VERSION 5.8 ;
BUSBITCHARS "[]" ;
DIVIDERCHAR "/" ;
UNITS
    DATABASE MICRONS 1000 ;
END UNITS

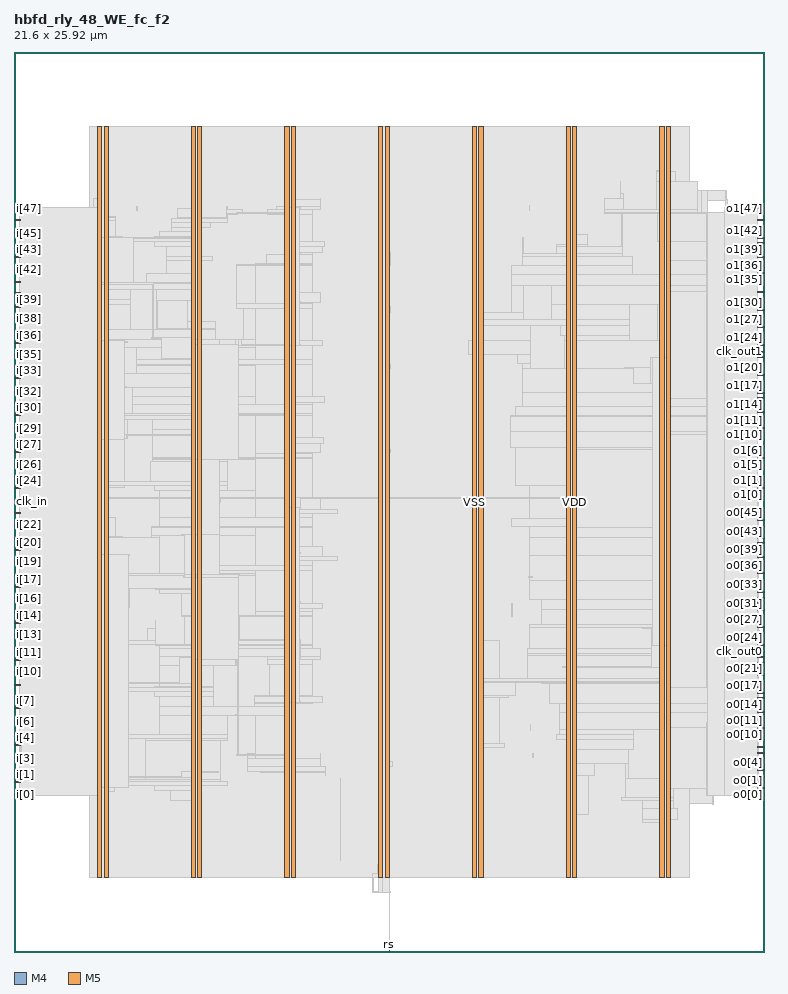
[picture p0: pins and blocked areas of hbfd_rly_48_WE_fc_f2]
MACRO hbfd_rly_48_WE_fc_f2
  FOREIGN hbfd_rly_48_WE_fc_f2 0 0 ;
  CLASS BLOCK ;
  SIZE 21.6 BY 25.92 ;
  PIN clk_in
    DIRECTION INPUT ;
    USE SIGNAL ;
    PORT
      LAYER M4 ;
        RECT  0 12.96 0.192 12.984 ;
    END
  END clk_in
  PIN clk_out0
    DIRECTION OUTPUT ;
    USE SIGNAL ;
    PORT
      LAYER M4 ;
        RECT  21.408 8.64 21.6 8.664 ;
    END
  END clk_out0
  PIN clk_out1
    DIRECTION OUTPUT ;
    USE SIGNAL ;
    PORT
      LAYER M4 ;
        RECT  21.408 17.28 21.6 17.304 ;
    END
  END clk_out1
  PIN i[0]
    DIRECTION INPUT ;
    USE SIGNAL ;
    PORT
      LAYER M4 ;
        RECT  0 4.512 0.192 4.536 ;
    END
  END i[0]
  PIN i[10]
    DIRECTION INPUT ;
    USE SIGNAL ;
    PORT
      LAYER M4 ;
        RECT  0 8.064 0.192 8.088 ;
    END
  END i[10]
  PIN i[11]
    DIRECTION INPUT ;
    USE SIGNAL ;
    PORT
      LAYER M4 ;
        RECT  0 8.4 0.192 8.424 ;
    END
  END i[11]
  PIN i[12]
    DIRECTION INPUT ;
    USE SIGNAL ;
    PORT
      LAYER M4 ;
        RECT  0 8.736 0.192 8.76 ;
    END
  END i[12]
  PIN i[13]
    DIRECTION INPUT ;
    USE SIGNAL ;
    PORT
      LAYER M4 ;
        RECT  0 9.12 0.192 9.144 ;
    END
  END i[13]
  PIN i[14]
    DIRECTION INPUT ;
    USE SIGNAL ;
    PORT
      LAYER M4 ;
        RECT  0 9.456 0.192 9.48 ;
    END
  END i[14]
  PIN i[15]
    DIRECTION INPUT ;
    USE SIGNAL ;
    PORT
      LAYER M4 ;
        RECT  0 9.792 0.192 9.816 ;
    END
  END i[15]
  PIN i[16]
    DIRECTION INPUT ;
    USE SIGNAL ;
    PORT
      LAYER M4 ;
        RECT  0 10.176 0.192 10.2 ;
    END
  END i[16]
  PIN i[17]
    DIRECTION INPUT ;
    USE SIGNAL ;
    PORT
      LAYER M4 ;
        RECT  0 10.512 0.192 10.536 ;
    END
  END i[17]
  PIN i[18]
    DIRECTION INPUT ;
    USE SIGNAL ;
    PORT
      LAYER M4 ;
        RECT  0 10.848 0.192 10.872 ;
    END
  END i[18]
  PIN i[19]
    DIRECTION INPUT ;
    USE SIGNAL ;
    PORT
      LAYER M4 ;
        RECT  0 11.232 0.192 11.256 ;
    END
  END i[19]
  PIN i[1]
    DIRECTION INPUT ;
    USE SIGNAL ;
    PORT
      LAYER M4 ;
        RECT  0 4.896 0.192 4.92 ;
    END
  END i[1]
  PIN i[20]
    DIRECTION INPUT ;
    USE SIGNAL ;
    PORT
      LAYER M4 ;
        RECT  0 11.568 0.192 11.592 ;
    END
  END i[20]
  PIN i[21]
    DIRECTION INPUT ;
    USE SIGNAL ;
    PORT
      LAYER M4 ;
        RECT  0 11.904 0.192 11.928 ;
    END
  END i[21]
  PIN i[22]
    DIRECTION INPUT ;
    USE SIGNAL ;
    PORT
      LAYER M4 ;
        RECT  0 12.288 0.192 12.312 ;
    END
  END i[22]
  PIN i[23]
    DIRECTION INPUT ;
    USE SIGNAL ;
    PORT
      LAYER M4 ;
        RECT  0 12.624 0.192 12.648 ;
    END
  END i[23]
  PIN i[24]
    DIRECTION INPUT ;
    USE SIGNAL ;
    PORT
      LAYER M4 ;
        RECT  0 13.344 0.192 13.368 ;
    END
  END i[24]
  PIN i[25]
    DIRECTION INPUT ;
    USE SIGNAL ;
    PORT
      LAYER M4 ;
        RECT  0 13.68 0.192 13.704 ;
    END
  END i[25]
  PIN i[26]
    DIRECTION INPUT ;
    USE SIGNAL ;
    PORT
      LAYER M4 ;
        RECT  0 14.016 0.192 14.04 ;
    END
  END i[26]
  PIN i[27]
    DIRECTION INPUT ;
    USE SIGNAL ;
    PORT
      LAYER M4 ;
        RECT  0 14.4 0.192 14.424 ;
    END
  END i[27]
  PIN i[28]
    DIRECTION INPUT ;
    USE SIGNAL ;
    PORT
      LAYER M4 ;
        RECT  0 14.736 0.192 14.76 ;
    END
  END i[28]
  PIN i[29]
    DIRECTION INPUT ;
    USE SIGNAL ;
    PORT
      LAYER M4 ;
        RECT  0 15.072 0.192 15.096 ;
    END
  END i[29]
  PIN i[2]
    DIRECTION INPUT ;
    USE SIGNAL ;
    PORT
      LAYER M4 ;
        RECT  0 5.232 0.192 5.256 ;
    END
  END i[2]
  PIN i[30]
    DIRECTION INPUT ;
    USE SIGNAL ;
    PORT
      LAYER M4 ;
        RECT  0 15.456 0.192 15.48 ;
    END
  END i[30]
  PIN i[31]
    DIRECTION INPUT ;
    USE SIGNAL ;
    PORT
      LAYER M4 ;
        RECT  0 15.792 0.192 15.816 ;
    END
  END i[31]
  PIN i[32]
    DIRECTION INPUT ;
    USE SIGNAL ;
    PORT
      LAYER M4 ;
        RECT  0 16.128 0.192 16.152 ;
    END
  END i[32]
  PIN i[33]
    DIRECTION INPUT ;
    USE SIGNAL ;
    PORT
      LAYER M4 ;
        RECT  0 16.512 0.192 16.536 ;
    END
  END i[33]
  PIN i[34]
    DIRECTION INPUT ;
    USE SIGNAL ;
    PORT
      LAYER M4 ;
        RECT  0 16.848 0.192 16.872 ;
    END
  END i[34]
  PIN i[35]
    DIRECTION INPUT ;
    USE SIGNAL ;
    PORT
      LAYER M4 ;
        RECT  0 17.184 0.192 17.208 ;
    END
  END i[35]
  PIN i[36]
    DIRECTION INPUT ;
    USE SIGNAL ;
    PORT
      LAYER M4 ;
        RECT  0 17.52 0.192 17.544 ;
    END
  END i[36]
  PIN i[37]
    DIRECTION INPUT ;
    USE SIGNAL ;
    PORT
      LAYER M4 ;
        RECT  0 17.904 0.192 17.928 ;
    END
  END i[37]
  PIN i[38]
    DIRECTION INPUT ;
    USE SIGNAL ;
    PORT
      LAYER M4 ;
        RECT  0 18.24 0.192 18.264 ;
    END
  END i[38]
  PIN i[39]
    DIRECTION INPUT ;
    USE SIGNAL ;
    PORT
      LAYER M4 ;
        RECT  0 18.576 0.192 18.6 ;
    END
  END i[39]
  PIN i[3]
    DIRECTION INPUT ;
    USE SIGNAL ;
    PORT
      LAYER M4 ;
        RECT  0 5.568 0.192 5.592 ;
    END
  END i[3]
  PIN i[40]
    DIRECTION INPUT ;
    USE SIGNAL ;
    PORT
      LAYER M4 ;
        RECT  0 18.96 0.192 18.984 ;
    END
  END i[40]
  PIN i[41]
    DIRECTION INPUT ;
    USE SIGNAL ;
    PORT
      LAYER M4 ;
        RECT  0 19.296 0.192 19.32 ;
    END
  END i[41]
  PIN i[42]
    DIRECTION INPUT ;
    USE SIGNAL ;
    PORT
      LAYER M4 ;
        RECT  0 19.632 0.192 19.656 ;
    END
  END i[42]
  PIN i[43]
    DIRECTION INPUT ;
    USE SIGNAL ;
    PORT
      LAYER M4 ;
        RECT  0 20.016 0.192 20.04 ;
    END
  END i[43]
  PIN i[44]
    DIRECTION INPUT ;
    USE SIGNAL ;
    PORT
      LAYER M4 ;
        RECT  0 20.352 0.192 20.376 ;
    END
  END i[44]
  PIN i[45]
    DIRECTION INPUT ;
    USE SIGNAL ;
    PORT
      LAYER M4 ;
        RECT  0 20.688 0.192 20.712 ;
    END
  END i[45]
  PIN i[46]
    DIRECTION INPUT ;
    USE SIGNAL ;
    PORT
      LAYER M4 ;
        RECT  0 21.072 0.192 21.096 ;
    END
  END i[46]
  PIN i[47]
    DIRECTION INPUT ;
    USE SIGNAL ;
    PORT
      LAYER M4 ;
        RECT  0 21.408 0.192 21.432 ;
    END
  END i[47]
  PIN i[4]
    DIRECTION INPUT ;
    USE SIGNAL ;
    PORT
      LAYER M4 ;
        RECT  0 5.952 0.192 5.976 ;
    END
  END i[4]
  PIN i[5]
    DIRECTION INPUT ;
    USE SIGNAL ;
    PORT
      LAYER M4 ;
        RECT  0 6.288 0.192 6.312 ;
    END
  END i[5]
  PIN i[6]
    DIRECTION INPUT ;
    USE SIGNAL ;
    PORT
      LAYER M4 ;
        RECT  0 6.624 0.192 6.648 ;
    END
  END i[6]
  PIN i[7]
    DIRECTION INPUT ;
    USE SIGNAL ;
    PORT
      LAYER M4 ;
        RECT  0 7.008 0.192 7.032 ;
    END
  END i[7]
  PIN i[8]
    DIRECTION INPUT ;
    USE SIGNAL ;
    PORT
      LAYER M4 ;
        RECT  0 7.344 0.192 7.368 ;
    END
  END i[8]
  PIN i[9]
    DIRECTION INPUT ;
    USE SIGNAL ;
    PORT
      LAYER M4 ;
        RECT  0 7.68 0.192 7.704 ;
    END
  END i[9]
  PIN o0[0]
    DIRECTION OUTPUT ;
    USE SIGNAL ;
    PORT
      LAYER M4 ;
        RECT  21.408 4.512 21.6 4.536 ;
    END
  END o0[0]
  PIN o0[10]
    DIRECTION OUTPUT ;
    USE SIGNAL ;
    PORT
      LAYER M4 ;
        RECT  21.408 6.24 21.6 6.264 ;
    END
  END o0[10]
  PIN o0[11]
    DIRECTION OUTPUT ;
    USE SIGNAL ;
    PORT
      LAYER M4 ;
        RECT  21.408 6.432 21.6 6.456 ;
    END
  END o0[11]
  PIN o0[12]
    DIRECTION OUTPUT ;
    USE SIGNAL ;
    PORT
      LAYER M4 ;
        RECT  21.408 6.576 21.6 6.6 ;
    END
  END o0[12]
  PIN o0[13]
    DIRECTION OUTPUT ;
    USE SIGNAL ;
    PORT
      LAYER M4 ;
        RECT  21.408 6.768 21.6 6.792 ;
    END
  END o0[13]
  PIN o0[14]
    DIRECTION OUTPUT ;
    USE SIGNAL ;
    PORT
      LAYER M4 ;
        RECT  21.408 6.912 21.6 6.936 ;
    END
  END o0[14]
  PIN o0[15]
    DIRECTION OUTPUT ;
    USE SIGNAL ;
    PORT
      LAYER M4 ;
        RECT  21.408 7.104 21.6 7.128 ;
    END
  END o0[15]
  PIN o0[16]
    DIRECTION OUTPUT ;
    USE SIGNAL ;
    PORT
      LAYER M4 ;
        RECT  21.408 7.296 21.6 7.32 ;
    END
  END o0[16]
  PIN o0[17]
    DIRECTION OUTPUT ;
    USE SIGNAL ;
    PORT
      LAYER M4 ;
        RECT  21.408 7.44 21.6 7.464 ;
    END
  END o0[17]
  PIN o0[18]
    DIRECTION OUTPUT ;
    USE SIGNAL ;
    PORT
      LAYER M4 ;
        RECT  21.408 7.632 21.6 7.656 ;
    END
  END o0[18]
  PIN o0[19]
    DIRECTION OUTPUT ;
    USE SIGNAL ;
    PORT
      LAYER M4 ;
        RECT  21.408 7.776 21.6 7.8 ;
    END
  END o0[19]
  PIN o0[1]
    DIRECTION OUTPUT ;
    USE SIGNAL ;
    PORT
      LAYER M4 ;
        RECT  21.408 4.704 21.6 4.728 ;
    END
  END o0[1]
  PIN o0[20]
    DIRECTION OUTPUT ;
    USE SIGNAL ;
    PORT
      LAYER M4 ;
        RECT  21.408 7.968 21.6 7.992 ;
    END
  END o0[20]
  PIN o0[21]
    DIRECTION OUTPUT ;
    USE SIGNAL ;
    PORT
      LAYER M4 ;
        RECT  21.408 8.16 21.6 8.184 ;
    END
  END o0[21]
  PIN o0[22]
    DIRECTION OUTPUT ;
    USE SIGNAL ;
    PORT
      LAYER M4 ;
        RECT  21.408 8.304 21.6 8.328 ;
    END
  END o0[22]
  PIN o0[23]
    DIRECTION OUTPUT ;
    USE SIGNAL ;
    PORT
      LAYER M4 ;
        RECT  21.408 8.496 21.6 8.52 ;
    END
  END o0[23]
  PIN o0[24]
    DIRECTION OUTPUT ;
    USE SIGNAL ;
    PORT
      LAYER M4 ;
        RECT  21.408 8.832 21.6 8.856 ;
    END
  END o0[24]
  PIN o0[25]
    DIRECTION OUTPUT ;
    USE SIGNAL ;
    PORT
      LAYER M4 ;
        RECT  21.408 8.976 21.6 9 ;
    END
  END o0[25]
  PIN o0[26]
    DIRECTION OUTPUT ;
    USE SIGNAL ;
    PORT
      LAYER M4 ;
        RECT  21.408 9.168 21.6 9.192 ;
    END
  END o0[26]
  PIN o0[27]
    DIRECTION OUTPUT ;
    USE SIGNAL ;
    PORT
      LAYER M4 ;
        RECT  21.408 9.36 21.6 9.384 ;
    END
  END o0[27]
  PIN o0[28]
    DIRECTION OUTPUT ;
    USE SIGNAL ;
    PORT
      LAYER M4 ;
        RECT  21.408 9.504 21.6 9.528 ;
    END
  END o0[28]
  PIN o0[29]
    DIRECTION OUTPUT ;
    USE SIGNAL ;
    PORT
      LAYER M4 ;
        RECT  21.408 9.696 21.6 9.72 ;
    END
  END o0[29]
  PIN o0[2]
    DIRECTION OUTPUT ;
    USE SIGNAL ;
    PORT
      LAYER M4 ;
        RECT  21.408 4.896 21.6 4.92 ;
    END
  END o0[2]
  PIN o0[30]
    DIRECTION OUTPUT ;
    USE SIGNAL ;
    PORT
      LAYER M4 ;
        RECT  21.408 9.84 21.6 9.864 ;
    END
  END o0[30]
  PIN o0[31]
    DIRECTION OUTPUT ;
    USE SIGNAL ;
    PORT
      LAYER M4 ;
        RECT  21.408 10.032 21.6 10.056 ;
    END
  END o0[31]
  PIN o0[32]
    DIRECTION OUTPUT ;
    USE SIGNAL ;
    PORT
      LAYER M4 ;
        RECT  21.408 10.176 21.6 10.2 ;
    END
  END o0[32]
  PIN o0[33]
    DIRECTION OUTPUT ;
    USE SIGNAL ;
    PORT
      LAYER M4 ;
        RECT  21.408 10.368 21.6 10.392 ;
    END
  END o0[33]
  PIN o0[34]
    DIRECTION OUTPUT ;
    USE SIGNAL ;
    PORT
      LAYER M4 ;
        RECT  21.408 10.56 21.6 10.584 ;
    END
  END o0[34]
  PIN o0[35]
    DIRECTION OUTPUT ;
    USE SIGNAL ;
    PORT
      LAYER M4 ;
        RECT  21.408 10.704 21.6 10.728 ;
    END
  END o0[35]
  PIN o0[36]
    DIRECTION OUTPUT ;
    USE SIGNAL ;
    PORT
      LAYER M4 ;
        RECT  21.408 10.896 21.6 10.92 ;
    END
  END o0[36]
  PIN o0[37]
    DIRECTION OUTPUT ;
    USE SIGNAL ;
    PORT
      LAYER M4 ;
        RECT  21.408 11.04 21.6 11.064 ;
    END
  END o0[37]
  PIN o0[38]
    DIRECTION OUTPUT ;
    USE SIGNAL ;
    PORT
      LAYER M4 ;
        RECT  21.408 11.232 21.6 11.256 ;
    END
  END o0[38]
  PIN o0[39]
    DIRECTION OUTPUT ;
    USE SIGNAL ;
    PORT
      LAYER M4 ;
        RECT  21.408 11.376 21.6 11.4 ;
    END
  END o0[39]
  PIN o0[3]
    DIRECTION OUTPUT ;
    USE SIGNAL ;
    PORT
      LAYER M4 ;
        RECT  21.408 5.04 21.6 5.064 ;
    END
  END o0[3]
  PIN o0[40]
    DIRECTION OUTPUT ;
    USE SIGNAL ;
    PORT
      LAYER M4 ;
        RECT  21.408 11.568 21.6 11.592 ;
    END
  END o0[40]
  PIN o0[41]
    DIRECTION OUTPUT ;
    USE SIGNAL ;
    PORT
      LAYER M4 ;
        RECT  21.408 11.76 21.6 11.784 ;
    END
  END o0[41]
  PIN o0[42]
    DIRECTION OUTPUT ;
    USE SIGNAL ;
    PORT
      LAYER M4 ;
        RECT  21.408 11.904 21.6 11.928 ;
    END
  END o0[42]
  PIN o0[43]
    DIRECTION OUTPUT ;
    USE SIGNAL ;
    PORT
      LAYER M4 ;
        RECT  21.408 12.096 21.6 12.12 ;
    END
  END o0[43]
  PIN o0[44]
    DIRECTION OUTPUT ;
    USE SIGNAL ;
    PORT
      LAYER M4 ;
        RECT  21.408 12.24 21.6 12.264 ;
    END
  END o0[44]
  PIN o0[45]
    DIRECTION OUTPUT ;
    USE SIGNAL ;
    PORT
      LAYER M4 ;
        RECT  21.408 12.432 21.6 12.456 ;
    END
  END o0[45]
  PIN o0[46]
    DIRECTION OUTPUT ;
    USE SIGNAL ;
    PORT
      LAYER M4 ;
        RECT  21.408 12.624 21.6 12.648 ;
    END
  END o0[46]
  PIN o0[47]
    DIRECTION OUTPUT ;
    USE SIGNAL ;
    PORT
      LAYER M4 ;
        RECT  21.408 12.768 21.6 12.792 ;
    END
  END o0[47]
  PIN o0[4]
    DIRECTION OUTPUT ;
    USE SIGNAL ;
    PORT
      LAYER M4 ;
        RECT  21.408 5.232 21.6 5.256 ;
    END
  END o0[4]
  PIN o0[5]
    DIRECTION OUTPUT ;
    USE SIGNAL ;
    PORT
      LAYER M4 ;
        RECT  21.408 5.376 21.6 5.4 ;
    END
  END o0[5]
  PIN o0[6]
    DIRECTION OUTPUT ;
    USE SIGNAL ;
    PORT
      LAYER M4 ;
        RECT  21.408 5.568 21.6 5.592 ;
    END
  END o0[6]
  PIN o0[7]
    DIRECTION OUTPUT ;
    USE SIGNAL ;
    PORT
      LAYER M4 ;
        RECT  21.408 5.712 21.6 5.736 ;
    END
  END o0[7]
  PIN o0[8]
    DIRECTION OUTPUT ;
    USE SIGNAL ;
    PORT
      LAYER M4 ;
        RECT  21.408 5.904 21.6 5.928 ;
    END
  END o0[8]
  PIN o0[9]
    DIRECTION OUTPUT ;
    USE SIGNAL ;
    PORT
      LAYER M4 ;
        RECT  21.408 6.096 21.6 6.12 ;
    END
  END o0[9]
  PIN o1[0]
    DIRECTION OUTPUT ;
    USE SIGNAL ;
    PORT
      LAYER M4 ;
        RECT  21.408 13.152 21.6 13.176 ;
    END
  END o1[0]
  PIN o1[10]
    DIRECTION OUTPUT ;
    USE SIGNAL ;
    PORT
      LAYER M4 ;
        RECT  21.408 14.88 21.6 14.904 ;
    END
  END o1[10]
  PIN o1[11]
    DIRECTION OUTPUT ;
    USE SIGNAL ;
    PORT
      LAYER M4 ;
        RECT  21.408 15.072 21.6 15.096 ;
    END
  END o1[11]
  PIN o1[12]
    DIRECTION OUTPUT ;
    USE SIGNAL ;
    PORT
      LAYER M4 ;
        RECT  21.408 15.216 21.6 15.24 ;
    END
  END o1[12]
  PIN o1[13]
    DIRECTION OUTPUT ;
    USE SIGNAL ;
    PORT
      LAYER M4 ;
        RECT  21.408 15.408 21.6 15.432 ;
    END
  END o1[13]
  PIN o1[14]
    DIRECTION OUTPUT ;
    USE SIGNAL ;
    PORT
      LAYER M4 ;
        RECT  21.408 15.552 21.6 15.576 ;
    END
  END o1[14]
  PIN o1[15]
    DIRECTION OUTPUT ;
    USE SIGNAL ;
    PORT
      LAYER M4 ;
        RECT  21.408 15.744 21.6 15.768 ;
    END
  END o1[15]
  PIN o1[16]
    DIRECTION OUTPUT ;
    USE SIGNAL ;
    PORT
      LAYER M4 ;
        RECT  21.408 15.936 21.6 15.96 ;
    END
  END o1[16]
  PIN o1[17]
    DIRECTION OUTPUT ;
    USE SIGNAL ;
    PORT
      LAYER M4 ;
        RECT  21.408 16.08 21.6 16.104 ;
    END
  END o1[17]
  PIN o1[18]
    DIRECTION OUTPUT ;
    USE SIGNAL ;
    PORT
      LAYER M4 ;
        RECT  21.408 16.272 21.6 16.296 ;
    END
  END o1[18]
  PIN o1[19]
    DIRECTION OUTPUT ;
    USE SIGNAL ;
    PORT
      LAYER M4 ;
        RECT  21.408 16.416 21.6 16.44 ;
    END
  END o1[19]
  PIN o1[1]
    DIRECTION OUTPUT ;
    USE SIGNAL ;
    PORT
      LAYER M4 ;
        RECT  21.408 13.344 21.6 13.368 ;
    END
  END o1[1]
  PIN o1[20]
    DIRECTION OUTPUT ;
    USE SIGNAL ;
    PORT
      LAYER M4 ;
        RECT  21.408 16.608 21.6 16.632 ;
    END
  END o1[20]
  PIN o1[21]
    DIRECTION OUTPUT ;
    USE SIGNAL ;
    PORT
      LAYER M4 ;
        RECT  21.408 16.8 21.6 16.824 ;
    END
  END o1[21]
  PIN o1[22]
    DIRECTION OUTPUT ;
    USE SIGNAL ;
    PORT
      LAYER M4 ;
        RECT  21.408 16.944 21.6 16.968 ;
    END
  END o1[22]
  PIN o1[23]
    DIRECTION OUTPUT ;
    USE SIGNAL ;
    PORT
      LAYER M4 ;
        RECT  21.408 17.136 21.6 17.16 ;
    END
  END o1[23]
  PIN o1[24]
    DIRECTION OUTPUT ;
    USE SIGNAL ;
    PORT
      LAYER M4 ;
        RECT  21.408 17.472 21.6 17.496 ;
    END
  END o1[24]
  PIN o1[25]
    DIRECTION OUTPUT ;
    USE SIGNAL ;
    PORT
      LAYER M4 ;
        RECT  21.408 17.616 21.6 17.64 ;
    END
  END o1[25]
  PIN o1[26]
    DIRECTION OUTPUT ;
    USE SIGNAL ;
    PORT
      LAYER M4 ;
        RECT  21.408 17.808 21.6 17.832 ;
    END
  END o1[26]
  PIN o1[27]
    DIRECTION OUTPUT ;
    USE SIGNAL ;
    PORT
      LAYER M4 ;
        RECT  21.408 18 21.6 18.024 ;
    END
  END o1[27]
  PIN o1[28]
    DIRECTION OUTPUT ;
    USE SIGNAL ;
    PORT
      LAYER M4 ;
        RECT  21.408 18.144 21.6 18.168 ;
    END
  END o1[28]
  PIN o1[29]
    DIRECTION OUTPUT ;
    USE SIGNAL ;
    PORT
      LAYER M4 ;
        RECT  21.408 18.336 21.6 18.36 ;
    END
  END o1[29]
  PIN o1[2]
    DIRECTION OUTPUT ;
    USE SIGNAL ;
    PORT
      LAYER M4 ;
        RECT  21.408 13.536 21.6 13.56 ;
    END
  END o1[2]
  PIN o1[30]
    DIRECTION OUTPUT ;
    USE SIGNAL ;
    PORT
      LAYER M4 ;
        RECT  21.408 18.48 21.6 18.504 ;
    END
  END o1[30]
  PIN o1[31]
    DIRECTION OUTPUT ;
    USE SIGNAL ;
    PORT
      LAYER M4 ;
        RECT  21.408 18.672 21.6 18.696 ;
    END
  END o1[31]
  PIN o1[32]
    DIRECTION OUTPUT ;
    USE SIGNAL ;
    PORT
      LAYER M4 ;
        RECT  21.408 18.816 21.6 18.84 ;
    END
  END o1[32]
  PIN o1[33]
    DIRECTION OUTPUT ;
    USE SIGNAL ;
    PORT
      LAYER M4 ;
        RECT  21.408 19.008 21.6 19.032 ;
    END
  END o1[33]
  PIN o1[34]
    DIRECTION OUTPUT ;
    USE SIGNAL ;
    PORT
      LAYER M4 ;
        RECT  21.408 19.2 21.6 19.224 ;
    END
  END o1[34]
  PIN o1[35]
    DIRECTION OUTPUT ;
    USE SIGNAL ;
    PORT
      LAYER M4 ;
        RECT  21.408 19.344 21.6 19.368 ;
    END
  END o1[35]
  PIN o1[36]
    DIRECTION OUTPUT ;
    USE SIGNAL ;
    PORT
      LAYER M4 ;
        RECT  21.408 19.536 21.6 19.56 ;
    END
  END o1[36]
  PIN o1[37]
    DIRECTION OUTPUT ;
    USE SIGNAL ;
    PORT
      LAYER M4 ;
        RECT  21.408 19.68 21.6 19.704 ;
    END
  END o1[37]
  PIN o1[38]
    DIRECTION OUTPUT ;
    USE SIGNAL ;
    PORT
      LAYER M4 ;
        RECT  21.408 19.872 21.6 19.896 ;
    END
  END o1[38]
  PIN o1[39]
    DIRECTION OUTPUT ;
    USE SIGNAL ;
    PORT
      LAYER M4 ;
        RECT  21.408 20.016 21.6 20.04 ;
    END
  END o1[39]
  PIN o1[3]
    DIRECTION OUTPUT ;
    USE SIGNAL ;
    PORT
      LAYER M4 ;
        RECT  21.408 13.68 21.6 13.704 ;
    END
  END o1[3]
  PIN o1[40]
    DIRECTION OUTPUT ;
    USE SIGNAL ;
    PORT
      LAYER M4 ;
        RECT  21.408 20.208 21.6 20.232 ;
    END
  END o1[40]
  PIN o1[41]
    DIRECTION OUTPUT ;
    USE SIGNAL ;
    PORT
      LAYER M4 ;
        RECT  21.408 20.4 21.6 20.424 ;
    END
  END o1[41]
  PIN o1[42]
    DIRECTION OUTPUT ;
    USE SIGNAL ;
    PORT
      LAYER M4 ;
        RECT  21.408 20.544 21.6 20.568 ;
    END
  END o1[42]
  PIN o1[43]
    DIRECTION OUTPUT ;
    USE SIGNAL ;
    PORT
      LAYER M4 ;
        RECT  21.408 20.736 21.6 20.76 ;
    END
  END o1[43]
  PIN o1[44]
    DIRECTION OUTPUT ;
    USE SIGNAL ;
    PORT
      LAYER M4 ;
        RECT  21.408 20.88 21.6 20.904 ;
    END
  END o1[44]
  PIN o1[45]
    DIRECTION OUTPUT ;
    USE SIGNAL ;
    PORT
      LAYER M4 ;
        RECT  21.408 21.072 21.6 21.096 ;
    END
  END o1[45]
  PIN o1[46]
    DIRECTION OUTPUT ;
    USE SIGNAL ;
    PORT
      LAYER M4 ;
        RECT  21.408 21.264 21.6 21.288 ;
    END
  END o1[46]
  PIN o1[47]
    DIRECTION OUTPUT ;
    USE SIGNAL ;
    PORT
      LAYER M4 ;
        RECT  21.408 21.408 21.6 21.432 ;
    END
  END o1[47]
  PIN o1[4]
    DIRECTION OUTPUT ;
    USE SIGNAL ;
    PORT
      LAYER M4 ;
        RECT  21.408 13.872 21.6 13.896 ;
    END
  END o1[4]
  PIN o1[5]
    DIRECTION OUTPUT ;
    USE SIGNAL ;
    PORT
      LAYER M4 ;
        RECT  21.408 14.016 21.6 14.04 ;
    END
  END o1[5]
  PIN o1[6]
    DIRECTION OUTPUT ;
    USE SIGNAL ;
    PORT
      LAYER M4 ;
        RECT  21.408 14.208 21.6 14.232 ;
    END
  END o1[6]
  PIN o1[7]
    DIRECTION OUTPUT ;
    USE SIGNAL ;
    PORT
      LAYER M4 ;
        RECT  21.408 14.352 21.6 14.376 ;
    END
  END o1[7]
  PIN o1[8]
    DIRECTION OUTPUT ;
    USE SIGNAL ;
    PORT
      LAYER M4 ;
        RECT  21.408 14.544 21.6 14.568 ;
    END
  END o1[8]
  PIN o1[9]
    DIRECTION OUTPUT ;
    USE SIGNAL ;
    PORT
      LAYER M4 ;
        RECT  21.408 14.736 21.6 14.76 ;
    END
  END o1[9]
  PIN rs
    DIRECTION INPUT ;
    USE SIGNAL ;
    PORT
      LAYER M5 ;
        RECT  10.8 0 10.824 0.192 ;
    END
  END rs
  PIN VDD
    DIRECTION INOUT ;
    USE POWER ;
    PORT
      LAYER M5 ;
        RECT  18.792 2.151 18.912 23.769 ;
        RECT  16.092 2.151 16.212 23.769 ;
        RECT  13.392 2.151 13.512 23.769 ;
        RECT  10.692 2.151 10.812 23.769 ;
        RECT  7.992 2.151 8.112 23.769 ;
        RECT  5.292 2.151 5.412 23.769 ;
        RECT  2.592 2.151 2.712 23.769 ;
    END
  END VDD
  PIN VSS
    DIRECTION INOUT ;
    USE GROUND ;
    PORT
      LAYER M5 ;
        RECT  18.6 2.137 18.72 23.783 ;
        RECT  15.9 2.137 16.02 23.783 ;
        RECT  13.2 2.137 13.32 23.783 ;
        RECT  10.5 2.137 10.62 23.783 ;
        RECT  7.8 2.137 7.92 23.783 ;
        RECT  5.1 2.137 5.22 23.783 ;
        RECT  2.4 2.137 2.52 23.783 ;
    END
  END VSS
  OBS
    LAYER RVTN ;
     RECT  2.16 2.16 19.44 2.295 ;
     RECT  2.16 2.565 19.44 2.835 ;
     RECT  2.16 3.105 19.44 3.375 ;
     RECT  2.16 3.645 19.44 3.915 ;
     RECT  2.16 4.185 19.44 4.455 ;
     RECT  2.16 4.725 19.44 4.995 ;
     RECT  2.16 5.265 19.44 5.535 ;
     RECT  2.16 5.805 19.44 6.075 ;
     RECT  2.16 6.345 19.44 6.615 ;
     RECT  2.16 6.885 19.44 7.155 ;
     RECT  2.16 7.425 19.44 7.695 ;
     RECT  2.16 7.965 19.44 8.235 ;
     RECT  2.16 8.505 19.44 8.775 ;
     RECT  2.16 9.045 19.44 9.315 ;
     RECT  2.16 9.585 19.44 9.855 ;
     RECT  2.16 10.125 19.44 10.395 ;
     RECT  2.16 10.665 19.44 10.935 ;
     RECT  2.16 11.205 19.44 11.475 ;
     RECT  2.16 11.745 19.44 12.015 ;
     RECT  2.16 12.285 19.44 12.555 ;
     RECT  2.16 12.825 19.44 13.095 ;
     RECT  2.16 13.365 19.44 13.635 ;
     RECT  2.16 13.905 19.44 14.175 ;
     RECT  2.16 14.445 19.44 14.715 ;
     RECT  2.16 14.985 19.44 15.255 ;
     RECT  2.16 15.525 19.44 15.795 ;
     RECT  2.16 16.065 19.44 16.335 ;
     RECT  2.16 16.605 19.44 16.875 ;
     RECT  2.16 17.145 19.44 17.415 ;
     RECT  2.16 17.685 19.44 17.955 ;
     RECT  2.16 18.225 19.44 18.495 ;
     RECT  2.16 18.765 19.44 19.035 ;
     RECT  2.16 19.305 19.44 19.575 ;
     RECT  2.16 19.845 19.44 20.115 ;
     RECT  2.16 20.385 19.44 20.655 ;
     RECT  2.16 20.925 19.44 21.195 ;
     RECT  2.16 21.465 19.44 21.735 ;
     RECT  2.16 22.005 19.44 22.275 ;
     RECT  2.16 22.545 19.44 22.815 ;
     RECT  2.16 23.085 19.44 23.355 ;
     RECT  2.16 23.625 19.44 23.76 ;
    LAYER RVTP ;
     RECT  2.16 2.295 19.44 2.565 ;
     RECT  2.16 2.835 19.44 3.105 ;
     RECT  2.16 3.375 19.44 3.645 ;
     RECT  2.16 3.915 19.44 4.185 ;
     RECT  2.16 4.455 19.44 4.725 ;
     RECT  2.16 4.995 19.44 5.265 ;
     RECT  2.16 5.535 19.44 5.805 ;
     RECT  2.16 6.075 19.44 6.345 ;
     RECT  2.16 6.615 19.44 6.885 ;
     RECT  2.16 7.155 19.44 7.425 ;
     RECT  2.16 7.695 19.44 7.965 ;
     RECT  2.16 8.235 19.44 8.505 ;
     RECT  2.16 8.775 19.44 9.045 ;
     RECT  2.16 9.315 19.44 9.585 ;
     RECT  2.16 9.855 19.44 10.125 ;
     RECT  2.16 10.395 19.44 10.665 ;
     RECT  2.16 10.935 19.44 11.205 ;
     RECT  2.16 11.475 19.44 11.745 ;
     RECT  2.16 12.015 19.44 12.285 ;
     RECT  2.16 12.555 19.44 12.825 ;
     RECT  2.16 13.095 19.44 13.365 ;
     RECT  2.16 13.635 19.44 13.905 ;
     RECT  2.16 14.175 19.44 14.445 ;
     RECT  2.16 14.715 19.44 14.985 ;
     RECT  2.16 15.255 19.44 15.525 ;
     RECT  2.16 15.795 19.44 16.065 ;
     RECT  2.16 16.335 19.44 16.605 ;
     RECT  2.16 16.875 19.44 17.145 ;
     RECT  2.16 17.415 19.44 17.685 ;
     RECT  2.16 17.955 19.44 18.225 ;
     RECT  2.16 18.495 19.44 18.765 ;
     RECT  2.16 19.035 19.44 19.305 ;
     RECT  2.16 19.575 19.44 19.845 ;
     RECT  2.16 20.115 19.44 20.385 ;
     RECT  2.16 20.655 19.44 20.925 ;
     RECT  2.16 21.195 19.44 21.465 ;
     RECT  2.16 21.735 19.44 22.005 ;
     RECT  2.16 22.275 19.44 22.545 ;
     RECT  2.16 22.815 19.44 23.085 ;
     RECT  2.16 23.355 19.44 23.625 ;
    LAYER M1 ;
     RECT  2.16 2.151 19.44 23.769 ;
    LAYER M2 ;
     RECT  0.211 14.76 2.16 14.778 ;
     RECT  0.211 19.35 2.16 19.368 ;
     RECT  2.16 2.151 19.44 23.769 ;
     RECT  19.44 17.856 19.679 22.194 ;
     RECT  19.679 17.856 19.787 21.924 ;
     RECT  19.44 14.526 19.967 16.524 ;
     RECT  19.787 17.928 19.967 21.924 ;
     RECT  19.967 18.576 20.003 20.844 ;
     RECT  19.44 4.266 20.147 11.934 ;
     RECT  20.003 18.702 20.255 20.844 ;
     RECT  20.147 4.896 20.507 11.934 ;
     RECT  19.967 21.636 20.507 21.924 ;
     RECT  20.507 4.896 20.543 5.904 ;
     RECT  20.507 6.966 20.543 7.722 ;
     RECT  20.507 10.908 20.543 11.934 ;
     RECT  19.967 14.526 20.543 15.516 ;
     RECT  20.255 18.702 20.543 20.484 ;
     RECT  20.507 21.636 20.543 21.654 ;
     RECT  20.507 8.586 20.579 8.604 ;
     RECT  20.507 9.828 20.579 9.846 ;
     RECT  20.543 11.214 20.579 11.304 ;
     RECT  20.543 14.994 20.579 15.444 ;
     RECT  19.967 16.308 20.579 16.524 ;
     RECT  20.543 19.206 20.579 19.224 ;
     RECT  20.579 15.426 20.615 15.444 ;
     RECT  19.44 12.906 21.379 12.924 ;
     RECT  21.379 12.456 21.407 12.924 ;
     RECT  21.307 14.841 21.407 14.859 ;
     RECT  20.579 16.506 21.407 16.524 ;
     RECT  20.543 4.896 21.443 4.914 ;
     RECT  21.379 9.171 21.479 9.189 ;
     RECT  21.407 12.456 21.479 12.474 ;
    LAYER M3 ;
     RECT  10.332 1.723 10.35 2.143 ;
     RECT  10.332 2.143 10.605 2.255 ;
     RECT  2.415 2.143 2.505 2.413 ;
     RECT  5.115 2.143 5.205 2.413 ;
     RECT  7.815 2.143 7.905 2.413 ;
     RECT  10.476 2.255 10.605 2.413 ;
     RECT  13.215 2.143 13.305 2.413 ;
     RECT  15.915 2.143 16.005 2.413 ;
     RECT  18.615 2.143 18.705 2.413 ;
     RECT  10.476 2.413 10.797 2.525 ;
     RECT  18.615 2.413 18.897 3.721 ;
     RECT  18.108 3.721 18.897 3.811 ;
     RECT  15.915 2.413 16.197 3.955 ;
     RECT  18.108 3.811 19.098 4.145 ;
     RECT  5.115 2.413 5.397 4.351 ;
     RECT  18.108 4.145 18.99 4.351 ;
     RECT  17.496 4.351 18.99 4.451 ;
     RECT  2.415 2.413 2.697 4.495 ;
     RECT  20.124 4.261 20.142 4.495 ;
     RECT  2.304 4.495 2.697 4.621 ;
     RECT  4.5 4.351 5.397 4.657 ;
     RECT  2.304 4.621 2.898 4.729 ;
     RECT  2.304 4.729 3.222 4.801 ;
     RECT  4.032 4.657 5.397 4.801 ;
     RECT  2.304 4.801 6.138 4.919 ;
     RECT  2.304 4.919 5.958 4.955 ;
     RECT  9.396 2.641 9.414 4.991 ;
     RECT  17.604 4.451 18.99 4.991 ;
     RECT  18.576 4.991 18.99 5.029 ;
     RECT  19.944 4.495 20.142 5.029 ;
     RECT  18.576 5.029 20.142 5.069 ;
     RECT  15.915 3.955 16.542 5.071 ;
     RECT  7.815 2.413 8.097 5.161 ;
     RECT  8.964 5.071 8.982 5.161 ;
     RECT  7.092 5.161 8.982 5.197 ;
     RECT  20.124 5.069 20.142 5.227 ;
     RECT  10.515 2.525 10.797 5.233 ;
     RECT  6.732 5.197 8.982 5.333 ;
     RECT  10.515 5.233 10.818 5.341 ;
     RECT  15.915 5.071 16.722 5.431 ;
     RECT  17.604 4.991 17.694 5.431 ;
     RECT  18.576 5.069 19.098 5.459 ;
     RECT  10.515 5.341 10.89 5.495 ;
     RECT  6.732 5.333 8.838 5.567 ;
     RECT  6.732 5.567 6.966 5.729 ;
     RECT  8.82 5.567 8.838 5.729 ;
     RECT  14.94 5.611 14.958 5.729 ;
     RECT  15.915 5.431 17.694 5.845 ;
     RECT  13.215 2.413 13.497 5.881 ;
     RECT  18.615 5.459 19.098 5.899 ;
     RECT  20.124 5.227 20.538 5.899 ;
     RECT  18.615 5.899 20.538 5.909 ;
     RECT  13.215 5.881 14.13 5.999 ;
     RECT  3.78 4.955 5.958 6.079 ;
     RECT  15.915 5.845 17.838 6.115 ;
     RECT  2.304 4.955 2.97 6.151 ;
     RECT  3.78 6.079 6.138 6.151 ;
     RECT  2.304 6.151 6.138 6.269 ;
     RECT  15.624 6.115 17.838 6.269 ;
     RECT  2.304 6.269 3.114 6.305 ;
     RECT  15.696 6.269 17.838 6.421 ;
     RECT  18.615 5.909 20.502 6.421 ;
     RECT  14.868 6.385 14.886 6.539 ;
     RECT  4.176 6.269 6.138 6.808 ;
     RECT  6.948 5.729 6.966 6.808 ;
     RECT  4.176 6.808 6.966 6.817 ;
     RECT  7.815 5.567 8.097 6.817 ;
     RECT  15.696 6.421 20.502 6.907 ;
     RECT  4.176 6.817 8.097 7.079 ;
     RECT  6.912 7.079 8.097 7.159 ;
     RECT  15.696 6.907 20.538 7.159 ;
     RECT  6.912 7.159 8.586 7.195 ;
     RECT  2.304 6.305 2.862 7.291 ;
     RECT  13.215 5.999 13.986 7.321 ;
     RECT  6.912 7.195 8.874 7.349 ;
     RECT  4.176 7.079 5.742 7.357 ;
     RECT  6.912 7.349 8.586 7.385 ;
     RECT  13.215 7.321 14.238 7.393 ;
     RECT  2.304 7.291 3.258 7.501 ;
     RECT  4.032 7.357 5.742 7.501 ;
     RECT  2.304 7.501 5.742 7.619 ;
     RECT  2.304 7.619 3.114 7.655 ;
     RECT  4.032 7.619 5.742 7.655 ;
     RECT  15.408 7.159 20.538 7.735 ;
     RECT  13.215 7.393 14.454 7.771 ;
     RECT  15.192 7.735 20.538 7.771 ;
     RECT  13.215 7.771 20.538 7.799 ;
     RECT  13.215 7.799 18.99 7.889 ;
     RECT  2.304 7.655 2.826 7.925 ;
     RECT  4.176 7.655 5.742 8.251 ;
     RECT  7.344 7.385 8.586 8.275 ;
     RECT  7.308 8.275 8.586 8.437 ;
     RECT  19.728 7.799 20.538 8.491 ;
     RECT  4.176 8.251 6.426 8.509 ;
     RECT  7.308 8.437 8.838 8.509 ;
     RECT  14.796 7.889 18.99 8.545 ;
     RECT  19.728 8.491 20.574 8.545 ;
     RECT  14.796 8.545 20.574 8.609 ;
     RECT  2.304 7.925 2.697 8.731 ;
     RECT  4.176 8.509 8.838 8.735 ;
     RECT  14.796 8.609 20.538 8.735 ;
     RECT  4.176 8.735 8.586 8.815 ;
     RECT  4.068 8.815 8.586 8.843 ;
     RECT  2.304 8.731 3.222 8.851 ;
     RECT  4.068 8.843 4.086 8.851 ;
     RECT  2.304 8.851 4.086 8.969 ;
     RECT  13.215 7.889 13.986 8.969 ;
     RECT  21.42 4.891 21.438 9.16 ;
     RECT  21.384 9.16 21.438 9.166 ;
     RECT  21.384 9.166 21.474 9.197 ;
     RECT  21.42 9.197 21.474 9.245 ;
     RECT  3.852 8.969 4.086 9.311 ;
     RECT  14.832 8.735 20.538 9.355 ;
     RECT  14.832 9.355 20.574 9.419 ;
     RECT  4.068 9.311 4.086 9.545 ;
     RECT  4.896 8.843 8.586 9.661 ;
     RECT  4.824 9.661 8.586 9.677 ;
     RECT  2.304 8.969 2.697 9.751 ;
     RECT  6.948 9.677 8.586 9.815 ;
     RECT  15.192 9.419 20.574 9.851 ;
     RECT  7.815 9.815 8.586 9.895 ;
     RECT  2.304 9.751 3.114 9.931 ;
     RECT  7.815 9.895 8.874 10.049 ;
     RECT  14.328 9.661 14.346 10.049 ;
     RECT  15.192 9.851 20.538 10.165 ;
     RECT  4.824 9.677 5.742 10.327 ;
     RECT  4.176 10.327 5.742 10.435 ;
     RECT  2.304 9.931 3.33 10.471 ;
     RECT  4.068 10.435 5.742 10.471 ;
     RECT  14.832 10.165 20.538 10.699 ;
     RECT  2.304 10.471 5.814 10.843 ;
     RECT  6.948 9.815 6.966 10.843 ;
     RECT  2.304 10.843 6.966 10.895 ;
     RECT  5.115 10.895 6.966 10.975 ;
     RECT  7.815 10.049 8.586 10.975 ;
     RECT  5.115 10.975 8.586 11.129 ;
     RECT  7.815 11.129 8.586 11.281 ;
     RECT  7.815 11.281 9.306 11.399 ;
     RECT  14.832 10.699 20.574 11.405 ;
     RECT  7.815 11.399 8.874 11.669 ;
     RECT  2.304 10.895 4.194 11.939 ;
     RECT  14.832 11.405 20.538 11.939 ;
     RECT  2.304 11.939 3.114 11.975 ;
     RECT  3.96 11.939 4.194 11.983 ;
     RECT  5.115 11.129 6.966 11.983 ;
     RECT  3.96 11.983 6.966 12.217 ;
     RECT  7.815 11.669 8.586 12.217 ;
     RECT  3.96 12.217 8.586 12.245 ;
     RECT  14.832 11.939 20.322 12.253 ;
     RECT  21.42 9.245 21.438 12.427 ;
     RECT  21.384 12.427 21.438 12.451 ;
     RECT  14.328 12.253 20.322 12.479 ;
     RECT  21.384 12.451 21.474 12.509 ;
     RECT  2.304 11.975 2.934 12.515 ;
     RECT  4.176 12.245 8.586 12.515 ;
     RECT  7.815 12.515 8.586 12.631 ;
     RECT  7.815 12.631 9.306 12.749 ;
     RECT  7.815 12.749 8.838 13.055 ;
     RECT  0.216 12.955 0.234 13.085 ;
     RECT  21.384 12.509 21.438 13.243 ;
     RECT  21.348 13.243 21.438 13.277 ;
     RECT  4.176 12.515 6.966 13.289 ;
     RECT  4.176 13.289 6.138 13.297 ;
     RECT  2.304 12.515 2.697 13.369 ;
     RECT  21.348 13.277 21.402 13.373 ;
     RECT  2.304 13.369 3.186 13.441 ;
     RECT  4.032 13.297 6.138 13.441 ;
     RECT  14.832 12.479 20.322 13.441 ;
     RECT  2.304 13.441 6.138 13.559 ;
     RECT  3.924 13.559 6.138 14.135 ;
     RECT  3.996 14.135 6.138 14.179 ;
     RECT  6.948 13.289 6.966 14.179 ;
     RECT  3.996 14.179 6.966 14.215 ;
     RECT  7.815 13.055 8.586 14.215 ;
     RECT  3.996 14.215 8.586 14.237 ;
     RECT  6.948 14.237 8.586 14.369 ;
     RECT  7.815 14.369 8.586 14.377 ;
     RECT  10.515 5.495 10.797 14.377 ;
     RECT  10.515 14.377 10.854 14.477 ;
     RECT  14.436 13.441 20.322 14.521 ;
     RECT  7.815 14.377 8.838 14.647 ;
     RECT  2.304 13.559 3.186 14.791 ;
     RECT  7.815 14.647 8.91 14.819 ;
     RECT  21.384 13.373 21.402 14.836 ;
     RECT  21.312 14.836 21.402 14.864 ;
     RECT  14.292 14.521 20.538 14.989 ;
     RECT  3.996 14.237 5.814 15.061 ;
     RECT  0.216 14.755 0.234 15.101 ;
     RECT  2.304 14.791 3.258 15.331 ;
     RECT  3.996 15.061 6.138 15.331 ;
     RECT  14.292 14.989 20.574 15.421 ;
     RECT  21.312 14.864 21.33 15.421 ;
     RECT  14.292 15.421 21.33 15.449 ;
     RECT  2.304 15.331 6.138 15.451 ;
     RECT  6.948 14.369 6.966 15.451 ;
     RECT  2.304 15.451 6.966 15.457 ;
     RECT  7.815 14.819 8.586 15.457 ;
     RECT  2.304 15.457 8.586 15.521 ;
     RECT  14.436 15.449 21.33 15.719 ;
     RECT  3.42 15.521 8.586 15.755 ;
     RECT  7.815 15.755 8.586 15.835 ;
     RECT  3.42 15.755 6.966 15.989 ;
     RECT  7.815 15.835 8.946 15.989 ;
     RECT  14.652 15.719 21.33 16.109 ;
     RECT  2.304 15.521 2.697 16.267 ;
     RECT  3.42 15.989 6.138 16.267 ;
     RECT  21.312 16.109 21.33 16.501 ;
     RECT  21.312 16.501 21.402 16.637 ;
     RECT  2.304 16.267 6.138 16.673 ;
     RECT  14.652 16.109 20.574 16.799 ;
     RECT  10.515 14.477 10.797 16.807 ;
     RECT  3.528 16.673 6.138 16.891 ;
     RECT  6.948 15.989 6.966 16.891 ;
     RECT  10.515 16.807 10.854 16.907 ;
     RECT  3.528 16.891 6.966 16.915 ;
     RECT  7.815 15.989 8.586 16.915 ;
     RECT  14.652 16.799 14.886 16.951 ;
     RECT  21.312 16.637 21.33 16.973 ;
     RECT  3.528 16.915 8.586 17.069 ;
     RECT  13.215 8.969 13.497 17.221 ;
     RECT  14.508 16.951 14.886 17.221 ;
     RECT  2.304 16.673 2.697 17.419 ;
     RECT  3.528 17.069 6.966 17.419 ;
     RECT  7.815 17.069 8.586 17.455 ;
     RECT  7.815 17.455 8.874 17.609 ;
     RECT  13.104 17.221 14.886 17.609 ;
     RECT  15.84 16.799 20.574 17.609 ;
     RECT  2.304 17.419 6.966 17.651 ;
     RECT  15.84 17.609 17.73 17.761 ;
     RECT  2.304 17.651 5.814 17.915 ;
     RECT  4.104 17.915 5.814 17.951 ;
     RECT  13.215 17.609 14.886 18.031 ;
     RECT  15.732 17.761 17.73 18.031 ;
     RECT  5.004 17.951 5.814 18.149 ;
     RECT  13.215 18.031 17.73 18.221 ;
     RECT  13.215 18.221 14.67 18.419 ;
     RECT  10.515 16.907 10.797 18.427 ;
     RECT  6.624 17.651 6.966 18.535 ;
     RECT  7.815 17.609 8.586 18.535 ;
     RECT  10.515 18.427 10.854 18.599 ;
     RECT  2.304 17.915 3.366 18.661 ;
     RECT  15.48 18.221 17.73 18.661 ;
     RECT  18.54 17.609 20.574 18.661 ;
     RECT  6.408 18.535 8.586 18.689 ;
     RECT  7.815 18.689 8.586 18.697 ;
     RECT  4.104 17.951 4.122 18.769 ;
     RECT  5.004 18.149 5.397 18.769 ;
     RECT  2.232 18.661 3.366 18.797 ;
     RECT  7.815 18.697 8.838 18.995 ;
     RECT  2.304 18.797 3.366 19.075 ;
     RECT  4.104 18.769 5.397 19.075 ;
     RECT  14.328 18.419 14.67 19.201 ;
     RECT  15.48 18.661 20.574 19.201 ;
     RECT  2.304 19.075 5.397 19.277 ;
     RECT  2.304 19.277 2.97 19.499 ;
     RECT  14.328 19.201 20.574 19.499 ;
     RECT  3.816 19.277 5.397 19.535 ;
     RECT  0.216 19.345 0.234 19.661 ;
     RECT  14.328 19.499 17.802 19.769 ;
     RECT  6.408 18.689 6.966 19.777 ;
     RECT  7.815 18.995 8.586 19.777 ;
     RECT  10.515 18.599 10.797 19.777 ;
     RECT  6.408 19.777 8.586 19.805 ;
     RECT  6.948 19.805 8.586 19.841 ;
     RECT  18.615 19.499 20.574 19.901 ;
     RECT  4.392 19.535 5.397 19.921 ;
     RECT  4.392 19.921 5.706 20.039 ;
     RECT  14.652 19.769 17.802 20.039 ;
     RECT  7.272 19.841 8.586 20.075 ;
     RECT  14.652 20.039 17.514 20.111 ;
     RECT  10.515 19.777 10.854 20.147 ;
     RECT  7.815 20.075 8.586 20.155 ;
     RECT  2.304 19.499 2.697 20.281 ;
     RECT  15.624 20.111 17.514 20.309 ;
     RECT  4.392 20.039 5.397 20.317 ;
     RECT  7.815 20.155 8.874 20.317 ;
     RECT  15.624 20.309 16.506 20.381 ;
     RECT  2.304 20.281 2.898 20.389 ;
     RECT  7.815 20.317 8.946 20.453 ;
     RECT  2.304 20.389 3.222 20.461 ;
     RECT  4.032 20.317 5.397 20.461 ;
     RECT  18.615 19.901 20.538 20.461 ;
     RECT  2.304 20.461 5.397 20.579 ;
     RECT  14.652 20.111 14.67 20.579 ;
     RECT  2.304 20.579 3.114 20.615 ;
     RECT  4.032 20.579 5.397 20.615 ;
     RECT  15.915 20.381 16.506 20.651 ;
     RECT  4.176 20.615 5.397 20.759 ;
     RECT  4.536 20.759 5.397 20.857 ;
     RECT  4.536 20.857 5.67 21.001 ;
     RECT  2.304 20.615 2.934 21.067 ;
     RECT  10.515 20.147 10.797 21.091 ;
     RECT  4.536 21.001 6.138 21.119 ;
     RECT  2.268 21.067 2.934 21.155 ;
     RECT  4.716 21.119 6.138 21.155 ;
     RECT  2.304 21.155 2.934 21.191 ;
     RECT  6.12 21.155 6.138 21.235 ;
     RECT  7.815 20.453 8.586 21.235 ;
     RECT  10.515 21.091 10.818 21.263 ;
     RECT  6.12 21.235 6.426 21.271 ;
     RECT  17.496 20.309 17.514 21.271 ;
     RECT  18.54 20.461 20.538 21.271 ;
     RECT  16.992 21.271 20.538 21.299 ;
     RECT  6.12 21.271 6.57 21.389 ;
     RECT  7.308 21.235 8.586 21.389 ;
     RECT  16.992 21.299 19.674 21.389 ;
     RECT  7.56 21.389 8.586 21.397 ;
     RECT  4.716 21.155 5.397 21.425 ;
     RECT  3.528 21.361 3.546 21.461 ;
     RECT  6.12 21.389 6.138 21.461 ;
     RECT  7.56 21.397 8.838 21.461 ;
     RECT  14.832 21.361 14.85 21.497 ;
     RECT  7.815 21.461 8.838 21.659 ;
     RECT  20.484 21.299 20.538 21.659 ;
     RECT  2.304 21.191 2.697 21.695 ;
     RECT  8.82 21.659 8.838 21.695 ;
     RECT  16.992 21.389 17.55 21.695 ;
     RECT  17.46 21.695 17.55 21.839 ;
     RECT  20.484 21.659 20.502 21.929 ;
     RECT  17.46 21.839 17.478 22.199 ;
     RECT  18.504 21.389 19.674 22.199 ;
     RECT  18.504 22.199 19.062 22.469 ;
     RECT  18.504 22.469 18.897 22.505 ;
     RECT  2.415 21.695 2.697 23.507 ;
     RECT  5.115 21.425 5.397 23.507 ;
     RECT  7.815 21.659 8.097 23.507 ;
     RECT  10.515 21.263 10.797 23.507 ;
     RECT  13.215 18.419 13.497 23.507 ;
     RECT  15.915 20.651 16.197 23.507 ;
     RECT  18.615 22.505 18.897 23.507 ;
     RECT  2.415 23.507 2.505 23.777 ;
     RECT  5.115 23.507 5.205 23.777 ;
     RECT  7.815 23.507 7.905 23.777 ;
     RECT  10.515 23.507 10.605 23.777 ;
     RECT  13.215 23.507 13.305 23.777 ;
     RECT  15.915 23.507 16.005 23.777 ;
     RECT  18.615 23.507 18.705 23.777 ;
    LAYER M4 ;
     RECT  0.156 4.512 2.408 21.432 ;
     RECT  2.408 2.148 2.512 23.772 ;
     RECT  2.512 2.418 2.704 23.502 ;
     RECT  2.704 14.784 3.241 14.904 ;
     RECT  2.704 16.272 3.244 16.296 ;
     RECT  2.704 17.568 3.269 17.592 ;
     RECT  2.704 4.752 3.299 5.064 ;
     RECT  2.704 6.192 3.299 6.216 ;
     RECT  2.704 7.296 3.299 7.752 ;
     RECT  2.704 8.736 3.299 8.76 ;
     RECT  2.704 10.32 3.299 10.344 ;
     RECT  2.704 11.424 3.313 11.448 ;
     RECT  3.973 17.664 4.237 17.688 ;
     RECT  3.299 7.728 4.777 7.752 ;
     RECT  3.299 5.04 4.813 5.064 ;
     RECT  4.813 5.04 5.108 5.208 ;
     RECT  4.777 7.728 5.108 8.472 ;
     RECT  4.885 10.8 5.108 10.824 ;
     RECT  4.813 12 5.108 12.024 ;
     RECT  2.704 13.056 5.108 13.08 ;
     RECT  3.241 14.88 5.108 14.904 ;
     RECT  4.237 17.088 5.108 17.688 ;
     RECT  2.704 19.248 5.108 19.272 ;
     RECT  2.704 20.544 5.108 20.568 ;
     RECT  5.108 2.148 5.212 23.772 ;
     RECT  5.212 2.418 5.404 23.502 ;
     RECT  5.404 5.184 5.897 5.208 ;
     RECT  5.404 12.96 5.939 13.08 ;
     RECT  5.404 8.448 6.38 8.472 ;
     RECT  5.404 17.088 6.38 17.64 ;
     RECT  6.38 8.256 6.421 8.472 ;
     RECT  6.397 9.648 6.421 9.672 ;
     RECT  6.38 6.816 6.467 6.84 ;
     RECT  6.421 8.256 6.467 9.672 ;
     RECT  6.38 16.896 6.467 17.64 ;
     RECT  6.467 8.976 6.481 9.672 ;
     RECT  6.397 10.848 6.481 10.872 ;
     RECT  6.397 14.208 6.481 14.232 ;
     RECT  6.467 17.472 6.545 17.64 ;
     RECT  6.421 5.664 7.808 5.688 ;
     RECT  6.481 8.976 7.808 9 ;
     RECT  5.939 13.056 7.808 13.08 ;
     RECT  5.404 15.456 7.808 15.48 ;
     RECT  6.545 17.472 7.808 17.496 ;
     RECT  6.397 21.264 7.808 21.288 ;
     RECT  7.808 2.148 7.912 23.772 ;
     RECT  7.912 2.418 8.104 23.502 ;
     RECT  8.104 7.2 8.243 7.224 ;
     RECT  8.104 8.448 8.243 9 ;
     RECT  8.104 10.08 8.243 10.104 ;
     RECT  8.104 11.472 8.243 11.496 ;
     RECT  8.104 12.768 8.243 13.08 ;
     RECT  8.104 17.472 8.243 17.496 ;
     RECT  8.104 18.72 8.243 18.744 ;
     RECT  8.104 20.112 8.243 20.136 ;
     RECT  8.104 21.408 8.243 21.432 ;
     RECT  10.321 1.728 10.508 1.752 ;
     RECT  8.243 13.056 10.508 13.08 ;
     RECT  10.508 1.728 10.612 23.772 ;
     RECT  10.612 1.728 10.804 23.502 ;
     RECT  10.804 1.728 10.835 1.752 ;
     RECT  10.804 13.056 13.208 13.08 ;
     RECT  13.208 2.148 13.312 23.772 ;
     RECT  13.312 2.418 13.504 23.502 ;
     RECT  14.821 10.8 14.933 10.824 ;
     RECT  15.793 8.208 15.908 8.232 ;
     RECT  13.504 13.056 15.908 13.08 ;
     RECT  15.908 2.148 16.012 23.772 ;
     RECT  16.012 2.418 16.204 23.502 ;
     RECT  17.593 16.8 17.845 16.824 ;
     RECT  17.845 16.368 18.341 16.824 ;
     RECT  16.204 8.208 18.373 8.232 ;
     RECT  18.097 9.312 18.373 9.336 ;
     RECT  18.373 8.208 18.608 9.336 ;
     RECT  16.204 12.24 18.608 14.472 ;
     RECT  18.341 16.368 18.608 17.112 ;
     RECT  18.608 2.148 18.712 23.772 ;
     RECT  18.712 2.418 18.904 23.502 ;
     RECT  18.904 4.704 19.933 6.456 ;
     RECT  18.904 7.632 19.933 14.904 ;
     RECT  18.904 15.936 19.933 19.032 ;
     RECT  19.933 4.512 19.969 6.6 ;
     RECT  19.933 7.632 19.969 21.288 ;
     RECT  19.969 4.512 20.473 21.288 ;
     RECT  20.473 4.512 21.42 21.432 ;
     RECT  21.42 12.48 21.449 13.272 ;
     RECT  21.42 9.216 21.485 9.24 ;
     RECT  21.449 12.48 21.485 12.504 ;
    LAYER M5 ;
     RECT  10.8 0.144 10.824 1.763 ;
     RECT  10.8 1.763 10.812 2.137 ;
     RECT  2.4 2.137 2.52 2.151 ;
     RECT  5.1 2.137 5.22 2.151 ;
     RECT  7.8 2.137 7.92 2.151 ;
     RECT  13.2 2.137 13.32 2.151 ;
     RECT  15.9 2.137 16.02 2.151 ;
     RECT  18.6 2.137 18.72 2.151 ;
     RECT  2.4 2.151 2.712 4.741 ;
     RECT  0.192 5.653 0.216 5.987 ;
     RECT  7.8 2.151 8.112 7.189 ;
     RECT  5.1 2.151 5.412 8.437 ;
     RECT  6.432 5.653 6.456 8.437 ;
     RECT  18.6 2.151 18.912 8.821 ;
     RECT  5.1 8.437 6.456 10.789 ;
     RECT  4.896 10.789 6.456 10.883 ;
     RECT  2.4 4.741 3.288 11.459 ;
     RECT  4.896 10.883 5.928 12.035 ;
     RECT  7.8 7.189 8.232 12.803 ;
     RECT  5.1 12.035 5.928 14.197 ;
     RECT  2.4 11.459 2.712 14.773 ;
     RECT  18.384 8.821 18.912 17.123 ;
     RECT  7.8 12.803 8.112 17.461 ;
     RECT  5.1 14.197 6.456 17.507 ;
     RECT  2.4 14.773 3.192 17.603 ;
     RECT  5.1 17.507 5.928 17.651 ;
     RECT  2.4 17.603 2.712 19.237 ;
     RECT  3.984 17.653 4.008 19.237 ;
     RECT  2.4 19.237 4.008 19.283 ;
     RECT  2.4 19.283 3.432 20.579 ;
     RECT  7.8 17.461 8.232 21.443 ;
     RECT  2.4 20.579 2.712 23.769 ;
     RECT  5.1 17.651 5.412 23.769 ;
     RECT  7.8 21.443 8.112 23.769 ;
     RECT  10.5 2.137 10.812 23.769 ;
     RECT  13.2 2.151 13.512 23.769 ;
     RECT  15.9 2.151 16.212 23.769 ;
     RECT  18.6 17.123 18.912 23.769 ;
     RECT  2.4 23.769 2.52 23.783 ;
     RECT  5.1 23.769 5.22 23.783 ;
     RECT  7.8 23.769 7.92 23.783 ;
     RECT  10.5 23.769 10.62 23.783 ;
     RECT  13.2 23.769 13.32 23.783 ;
     RECT  15.9 23.769 16.02 23.783 ;
     RECT  18.6 23.769 18.72 23.783 ;
  END
END hbfd_rly_48_WE_fc_f2
END LIBRARY
